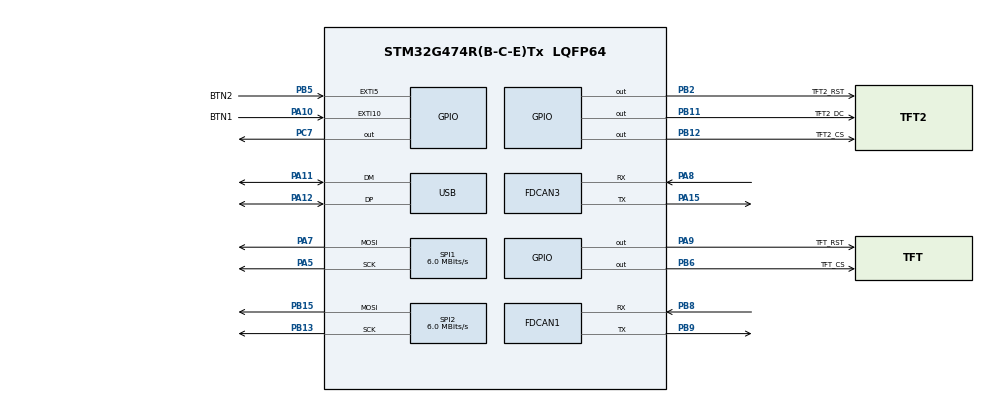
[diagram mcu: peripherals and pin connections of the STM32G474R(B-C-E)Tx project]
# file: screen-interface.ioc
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FDCAN1.CalculateBaudRateNominal=282352
FDCAN1.CalculateTimeBitNominal=3541
FDCAN1.CalculateTimeQuantumNominal=177.08333333333331
FDCAN1.NominalPrescaler=17
FDCAN1.NominalSyncJumpWidth=4
FDCAN1.NominalTimeSeg1=15
FDCAN1.NominalTimeSeg2=4
FDCAN3.CalculateBaudRateNominal=282352
FDCAN3.CalculateTimeBitNominal=3541
FDCAN3.CalculateTimeQuantumNominal=177.08333333333331
FDCAN3.NominalPrescaler=17
FDCAN3.NominalSyncJumpWidth=4
FDCAN3.NominalTimeSeg1=15
FDCAN3.NominalTimeSeg2=4
Mcu.Family=STM32G4
Mcu.Name=STM32G474R(B-C-E)Tx
Mcu.Package=LQFP64
NUCLEO-G474RE.BUTTON=1
NUCLEO-G474RE.LD2=false
NUCLEO-G474RE.VCP=true
NVIC.EXTI15_10_IRQn=true\:0\:0\:false\:false\:true\:false\:true\:true
NVIC.EXTI9_5_IRQn=true\:0\:0\:false\:false\:true\:true\:true\:true
NVIC.FDCAN1_IT0_IRQn=true\:0\:0\:false\:false\:true\:true\:true\:true
NVIC.FDCAN3_IT0_IRQn=true\:0\:0\:false\:false\:true\:true\:true\:true
NVIC.PriorityGroup=NVIC_PRIORITYGROUP_4
PA10.GPIO_Label=BTN1
PA10.GPIO_ModeDefaultEXTI=GPIO_MODE_IT_RISING
PA10.GPIO_PuPd=GPIO_PULLDOWN
PA10.Signal=GPXTI10
PA11.Mode=Device
PA11.Signal=USB_DM
PA12.Mode=Device
PA12.Signal=USB_DP
PA13.GPIO_Label=T_SWDIO
PA13.Signal=SYS_JTMS-SWDIO
PA14.GPIO_Label=T_SWCLK
PA14.Signal=SYS_JTCK-SWCLK
PA15.Mode=FDCAN_Activate
PA15.Signal=FDCAN3_TX
PA2.Signal=LPUART1_TX
PA3.Signal=LPUART1_RX
PA5.GPIO_Speed=GPIO_SPEED_FREQ_VERY_HIGH
PA5.Mode=TX_Only_Simplex_Unidirect_Master
PA5.Signal=SPI1_SCK
PA7.GPIO_Speed=GPIO_SPEED_FREQ_VERY_HIGH
PA7.Mode=TX_Only_Simplex_Unidirect_Master
PA7.Signal=SPI1_MOSI
PA8.Mode=FDCAN_Activate
PA8.Signal=FDCAN3_RX
PA9.GPIO_Label=TFT_RST
PA9.GPIO_Speed=GPIO_SPEED_FREQ_VERY_HIGH
PA9.PinState=GPIO_PIN_SET
PA9.Signal=GPIO_Output
PB11.GPIO_Label=TFT2_DC
PB11.GPIO_Speed=GPIO_SPEED_FREQ_VERY_HIGH
PB11.PinState=GPIO_PIN_SET
PB11.Signal=GPIO_Output
PB12.GPIO_Label=TFT2_CS
PB12.GPIO_Speed=GPIO_SPEED_FREQ_VERY_HIGH
PB12.PinState=GPIO_PIN_SET
PB12.Signal=GPIO_Output
PB13.GPIO_Speed=GPIO_SPEED_FREQ_VERY_HIGH
PB13.Mode=TX_Only_Simplex_Unidirect_Master
PB13.Signal=SPI2_SCK
PB15.GPIO_Speed=GPIO_SPEED_FREQ_VERY_HIGH
PB15.Mode=TX_Only_Simplex_Unidirect_Master
PB15.Signal=SPI2_MOSI
PB2.GPIO_Label=TFT2_RST
PB2.GPIO_Speed=GPIO_SPEED_FREQ_VERY_HIGH
PB2.PinState=GPIO_PIN_SET
PB2.Signal=GPIO_Output
PB3.GPIO_Label=T_SWO
PB3.Signal=SYS_JTDO-SWO
PB5.GPIO_Label=BTN2
PB5.GPIO_ModeDefaultEXTI=GPIO_MODE_IT_RISING
PB5.GPIO_PuPd=GPIO_PULLDOWN
PB5.Signal=GPXTI5
PB6.GPIO_Label=TFT_CS
PB6.GPIO_Speed=GPIO_SPEED_FREQ_VERY_HIGH
PB6.PinState=GPIO_PIN_SET
PB6.Signal=GPIO_Output
PB8-BOOT0.Mode=FDCAN_Activate
PB8-BOOT0.Signal=FDCAN1_RX
PB9.Mode=FDCAN_Activate
PB9.Signal=FDCAN1_TX
PC14-OSC32_IN.GPIO_Label=RCC_OSC32_IN
PC14-OSC32_IN.Signal=RCC_OSC32_IN
PC15-OSC32_OUT.GPIO_Label=RCC_OSC32_OUT
PC15-OSC32_OUT.Signal=RCC_OSC32_OUT
PC7.Signal=GPIO_Output
PF0-OSC_IN.GPIO_Label=RCC_OSC_IN
PF0-OSC_IN.Signal=RCC_OSC_IN
PF1-OSC_OUT.GPIO_Label=RCC_OSC_OUT
PF1-OSC_OUT.Signal=RCC_OSC_OUT
ProjectManager.HeapSize=0x200
ProjectManager.StackSize=0x400
ProjectManager.TargetToolchain=CMake
RCC.ADC12Freq_Value=96000000
RCC.ADC345Freq_Value=96000000
RCC.AHBFreq_Value=96000000
RCC.APB1Freq_Value=96000000
RCC.APB1TimFreq_Value=96000000
RCC.APB2Freq_Value=96000000
RCC.APB2TimFreq_Value=96000000
RCC.CortexFreq_Value=96000000
RCC.EXTERNAL_CLOCK_VALUE=12288000
RCC.HCLKFreq_Value=96000000
RCC.HSE_VALUE=24000000
RCC.HSI48_VALUE=48000000
RCC.HSI_VALUE=16000000
RCC.LSE_VALUE=32768
RCC.PLLN=12
RCC.PLLQ=RCC_PLLQ_DIV4
RCC.RTCClockSelection=RCC_RTCCLKSOURCE_LSE
RCC.SYSCLKFreq_VALUE=96000000
RCC.SYSCLKSource=RCC_SYSCLKSOURCE_PLLCLK
RCC.USBFreq_Value=48000000
RCC.VCOOutputFreq_Value=192000000
SPI1.BaudRatePrescaler=SPI_BAUDRATEPRESCALER_16
SPI1.CalculateBaudRate=6.0 MBits/s
SPI1.DataSize=SPI_DATASIZE_8BIT
SPI1.Direction=SPI_DIRECTION_2LINES
SPI1.Mode=SPI_MODE_MASTER
SPI1.VirtualType=VM_MASTER
SPI2.BaudRatePrescaler=SPI_BAUDRATEPRESCALER_16
SPI2.CalculateBaudRate=6.0 MBits/s
SPI2.DataSize=SPI_DATASIZE_8BIT
SPI2.Direction=SPI_DIRECTION_2LINES
SPI2.Mode=SPI_MODE_MASTER
SPI2.VirtualType=VM_MASTER
VP_NUCLEO-G474RE_VS_BSP_COMMON.Mode=COMMON
VP_SYS_VS_DBSignals.Mode=DisableDeadBatterySignals
board=NUCLEO-G474RE

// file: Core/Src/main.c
/* USER CODE BEGIN Header */
/**
  ******************************************************************************
  * @file           : main.c
  * @brief          : Main program body
  ******************************************************************************
  * @attention
  *
  * Copyright (c) 2026 STMicroelectronics.
  * All rights reserved.
  *
  * This software is licensed under terms that can be found in the LICENSE file
  * in the root directory of this software component.
  * If no LICENSE file comes with this software, it is provided AS-IS.
  *
  ******************************************************************************
  */
/* USER CODE END Header */
#include "main.h"

/* USER CODE BEGIN Includes */
#include "lvgl.h"
#include "lcd_port.h"
#include "dash_ui.h"
#include "dash_mock.h"
#include "can_bus.h"
/* USER CODE END Includes */

/* USER CODE BEGIN PD */
/* A CAN bus counts as alive if it received a frame this recently. */
#define CAN_ACTIVE_TIMEOUT_MS   500U

/* Longest the main loop sleeps, so received CAN frames are handled promptly
   and the software queues (can_bus.c) do not fill up. */
#define MAIN_LOOP_MAX_IDLE_MS   5U

#define CAN_NOTIFICATION_ID     0x123U
#define CAN_USER_BUTTON_ID_2    0x456U

/* BNO055 IMU frames, as sent by stm/can-frame-test. Standard IDs; each
   payload is three little-endian int16 raw BNO055 counts:
     0x100 accel x, y, z           100 LSB per m/s^2   (6 bytes)
     0x101 gyro  x, y, z            16 LSB per deg/s   (6 bytes)
     0x102 mag   x, y, z            16 LSB per uT      (6 bytes)
     0x103 heading, roll, pitch     16 LSB per degree, byte 6 = CALIB_STAT
           (sys | gyro | accel | mag, 2 bits each), byte 7 = 7-bit I2C
           address the IMU answered at                 (8 bytes)
   The IDs are consecutive and in dash_imu_t order. A 7-byte 0x103 (older
   sender firmware, no address) is still decoded; the address shows "0x--". */
#define CAN_ID_IMU_FIRST        0x100U
#define IMU_CALIB_FRAME_LEN     7U
#define IMU_ADDR_FRAME_LEN      8U
#define IMU_FRAME_LEN           6U

/* An IMU row shows "--" if its frame is older than this. */
#define IMU_TIMEOUT_MS          500U

/* The IMU sends at 100 Hz; redraw its readout at 10 Hz so the numbers can
   be read and the SPI link is not kept busy. */
#define IMU_UI_PERIOD_MS        100U

/* After a counted press, further edges on the same button are ignored for
   this long, so contact bounce and quick re-presses count once. */
#define BUTTON_DEBOUNCE_MS      500U
/* USER CODE END PD */

COM_InitTypeDef BspCOMInit;
FDCAN_HandleTypeDef hfdcan1;
FDCAN_HandleTypeDef hfdcan3;

SPI_HandleTypeDef hspi1;
SPI_HandleTypeDef hspi2;

/* USER CODE BEGIN PV */
/* Main display (speed, state of charge, status, IMU) on SPI1. */
static const lcd_port_t s_lcd_main = {
  .hspi = &hspi1,
  .cs_port = TFT_CS_GPIO_Port,   .cs_pin = TFT_CS_Pin,
  .dc_port = TFT_DC_GPIO_Port,   .dc_pin = TFT_DC_Pin,
  .rst_port = TFT_RST_GPIO_Port, .rst_pin = TFT_RST_Pin,
};

/* Second display (temperatures, CAN status) on SPI2. */
static const lcd_port_t s_lcd_aux = {
  .hspi = &hspi2,
  .cs_port = TFT2_CS_GPIO_Port,   .cs_pin = TFT2_CS_Pin,
  .dc_port = TFT2_DC_GPIO_Port,   .dc_pin = TFT2_DC_Pin,
  .rst_port = TFT2_RST_GPIO_Port, .rst_pin = TFT2_RST_Pin,
};

/* Latest IMU frame of each kind, raw counts. */
typedef struct
{
  int16_t  raw[3];
  uint32_t rx_tick;
  bool     seen;
} imu_sample_t;

static imu_sample_t s_imu[DASH_IMU_COUNT];
static uint8_t s_imu_calib_stat;
static int32_t s_imu_addr = DASH_NO_DATA;  /* 7-bit I2C address, from 0x103 */

/* Raw counts per unit, in dash_imu_t order. */
static const int32_t k_imu_lsb_per_unit[DASH_IMU_COUNT] = {100, 16, 16, 16};

/* Button presses counted by the EXTI interrupt (BTN1 = PA10, BTN2 = PB5),
   in dash_btn_t order. Written only in the interrupt, read in the main loop. */
static volatile uint32_t s_btn_count[DASH_BTN_COUNT];
/* Tick of the last counted press. Starts one debounce period in the past so
   a press right after reset still counts. */
static uint32_t s_btn_last_ms[DASH_BTN_COUNT] = {
  0U - BUTTON_DEBOUNCE_MS, 0U - BUTTON_DEBOUNCE_MS,
};
/* USER CODE END PV */

void SystemClock_Config(void);
static void MX_GPIO_Init(void);
static void MX_SPI1_Init(void);
static void MX_FDCAN1_Init(void);
static void MX_FDCAN3_Init(void);
static void MX_SPI2_Init(void);
/* USER CODE BEGIN PFP */
static void gui_init(void);
static void can_poll(void);
static void handle_can_frame(can_bus_t bus, const can_frame_t *frame);
static bool handle_imu_frame(const can_frame_t *frame);
static void imu_show(void);
static void buttons_show(void);
/* USER CODE END PFP */

int main(void)
{

  /* MCU Configuration--------------------------------------------------------*/

  /* Reset of all peripherals, Initializes the Flash interface and the Systick. */
  HAL_Init();

  /* Configure the system clock */
  SystemClock_Config();

  /* Initialize all configured peripherals */
  MX_GPIO_Init();
  MX_SPI1_Init();
  MX_FDCAN1_Init();
  MX_FDCAN3_Init();
  MX_SPI2_Init();
  /* USER CODE BEGIN 2 */
  gui_init();

  if (!can_bus_init(&hfdcan1, &hfdcan3))
  {
    Error_Handler();
  }
  /* USER CODE END 2 */

  /* Initialize USER push-button, will be used to trigger an interrupt each time it's pressed.*/
  BSP_PB_Init(BUTTON_USER, BUTTON_MODE_EXTI);

  /* Initialize COM1 port (115200, 8 bits (7-bit data + 1 stop bit), no parity */
  BspCOMInit.BaudRate   = 115200;
  BspCOMInit.WordLength = COM_WORDLENGTH_8B;
  BspCOMInit.StopBits   = COM_STOPBITS_1;
  BspCOMInit.Parity     = COM_PARITY_NONE;
  BspCOMInit.HwFlowCtl  = COM_HWCONTROL_NONE;
  if (BSP_COM_Init(COM1, &BspCOMInit) != BSP_ERROR_NONE)
  {
    Error_Handler();
  }

  /* Infinite loop */
  while (1)
  {

    /* USER CODE BEGIN 3 */
    can_poll();
    buttons_show();

    /* Runs LVGL's timers: refresh of both screens and the dashboard's mock
       data. Sleep until the next one is due, but not so long that CAN frames
       pile up. */
    uint32_t idle_ms = lv_timer_handler();

    if ((idle_ms == LV_NO_TIMER_READY) || (idle_ms > MAIN_LOOP_MAX_IDLE_MS))
    {
      idle_ms = MAIN_LOOP_MAX_IDLE_MS;
    }
    HAL_Delay(idle_ms);
  }
  /* USER CODE END 3 */
}

void SystemClock_Config(void)
{
  RCC_OscInitTypeDef RCC_OscInitStruct = {0};
  RCC_ClkInitTypeDef RCC_ClkInitStruct = {0};

  /** Configure the main internal regulator output voltage
  */
  HAL_PWREx_ControlVoltageScaling(PWR_REGULATOR_VOLTAGE_SCALE1_BOOST);

  /** Initializes the RCC Oscillators according to the specified parameters
  * in the RCC_OscInitTypeDef structure.
  */
  RCC_OscInitStruct.OscillatorType = RCC_OSCILLATORTYPE_HSI;
  RCC_OscInitStruct.HSIState = RCC_HSI_ON;
  RCC_OscInitStruct.HSICalibrationValue = RCC_HSICALIBRATION_DEFAULT;
  RCC_OscInitStruct.PLL.PLLState = RCC_PLL_ON;
  RCC_OscInitStruct.PLL.PLLSource = RCC_PLLSOURCE_HSI;
  RCC_OscInitStruct.PLL.PLLM = RCC_PLLM_DIV4;
  RCC_OscInitStruct.PLL.PLLN = 85;
  RCC_OscInitStruct.PLL.PLLP = RCC_PLLP_DIV2;
  RCC_OscInitStruct.PLL.PLLQ = RCC_PLLQ_DIV2;
  RCC_OscInitStruct.PLL.PLLR = RCC_PLLR_DIV2;
  if (HAL_RCC_OscConfig(&RCC_OscInitStruct) != HAL_OK)
  {
    Error_Handler();
  }

  /** Initializes the CPU, AHB and APB buses clocks
  */
  RCC_ClkInitStruct.ClockType = RCC_CLOCKTYPE_HCLK|RCC_CLOCKTYPE_SYSCLK
                              |RCC_CLOCKTYPE_PCLK1|RCC_CLOCKTYPE_PCLK2;
  RCC_ClkInitStruct.SYSCLKSource = RCC_SYSCLKSOURCE_PLLCLK;
  RCC_ClkInitStruct.AHBCLKDivider = RCC_SYSCLK_DIV1;
  RCC_ClkInitStruct.APB1CLKDivider = RCC_HCLK_DIV1;
  RCC_ClkInitStruct.APB2CLKDivider = RCC_HCLK_DIV1;

  if (HAL_RCC_ClockConfig(&RCC_ClkInitStruct, FLASH_LATENCY_4) != HAL_OK)
  {
    Error_Handler();
  }
}

static void MX_FDCAN1_Init(void)
{

  hfdcan1.Instance = FDCAN1;
  hfdcan1.Init.ClockDivider = FDCAN_CLOCK_DIV1;
  hfdcan1.Init.FrameFormat = FDCAN_FRAME_CLASSIC;
  hfdcan1.Init.Mode = FDCAN_MODE_NORMAL;
  hfdcan1.Init.AutoRetransmission = DISABLE;
  hfdcan1.Init.TransmitPause = DISABLE;
  hfdcan1.Init.ProtocolException = DISABLE;
  hfdcan1.Init.NominalPrescaler = 17;
  hfdcan1.Init.NominalSyncJumpWidth = 4;
  hfdcan1.Init.NominalTimeSeg1 = 15;
  hfdcan1.Init.NominalTimeSeg2 = 4;
  hfdcan1.Init.DataPrescaler = 1;
  hfdcan1.Init.DataSyncJumpWidth = 1;
  hfdcan1.Init.DataTimeSeg1 = 1;
  hfdcan1.Init.DataTimeSeg2 = 1;
  hfdcan1.Init.StdFiltersNbr = 0;
  hfdcan1.Init.ExtFiltersNbr = 0;
  hfdcan1.Init.TxFifoQueueMode = FDCAN_TX_FIFO_OPERATION;
  if (HAL_FDCAN_Init(&hfdcan1) != HAL_OK)
  {
    Error_Handler();
  }

}

static void MX_FDCAN3_Init(void)
{

  hfdcan3.Instance = FDCAN3;
  hfdcan3.Init.ClockDivider = FDCAN_CLOCK_DIV1;
  hfdcan3.Init.FrameFormat = FDCAN_FRAME_CLASSIC;
  hfdcan3.Init.Mode = FDCAN_MODE_NORMAL;
  hfdcan3.Init.AutoRetransmission = DISABLE;
  hfdcan3.Init.TransmitPause = DISABLE;
  hfdcan3.Init.ProtocolException = DISABLE;
  hfdcan3.Init.NominalPrescaler = 17;
  hfdcan3.Init.NominalSyncJumpWidth = 4;
  hfdcan3.Init.NominalTimeSeg1 = 15;
  hfdcan3.Init.NominalTimeSeg2 = 4;
  hfdcan3.Init.DataPrescaler = 1;
  hfdcan3.Init.DataSyncJumpWidth = 1;
  hfdcan3.Init.DataTimeSeg1 = 1;
  hfdcan3.Init.DataTimeSeg2 = 1;
  hfdcan3.Init.StdFiltersNbr = 0;
  hfdcan3.Init.ExtFiltersNbr = 0;
  hfdcan3.Init.TxFifoQueueMode = FDCAN_TX_FIFO_OPERATION;
  if (HAL_FDCAN_Init(&hfdcan3) != HAL_OK)
  {
    Error_Handler();
  }

}

static void MX_SPI1_Init(void)
{

  /* SPI1 parameter configuration*/
  hspi1.Instance = SPI1;
  hspi1.Init.Mode = SPI_MODE_MASTER;
  hspi1.Init.Direction = SPI_DIRECTION_2LINES;
  hspi1.Init.DataSize = SPI_DATASIZE_8BIT;
  hspi1.Init.CLKPolarity = SPI_POLARITY_LOW;
  hspi1.Init.CLKPhase = SPI_PHASE_1EDGE;
  hspi1.Init.NSS = SPI_NSS_SOFT;
  hspi1.Init.BaudRatePrescaler = SPI_BAUDRATEPRESCALER_16;
  hspi1.Init.FirstBit = SPI_FIRSTBIT_MSB;
  hspi1.Init.TIMode = SPI_TIMODE_DISABLE;
  hspi1.Init.CRCCalculation = SPI_CRCCALCULATION_DISABLE;
  hspi1.Init.CRCPolynomial = 7;
  hspi1.Init.CRCLength = SPI_CRC_LENGTH_DATASIZE;
  hspi1.Init.NSSPMode = SPI_NSS_PULSE_ENABLE;
  if (HAL_SPI_Init(&hspi1) != HAL_OK)
  {
    Error_Handler();
  }

}

static void MX_SPI2_Init(void)
{

  /* SPI2 parameter configuration*/
  hspi2.Instance = SPI2;
  hspi2.Init.Mode = SPI_MODE_MASTER;
  hspi2.Init.Direction = SPI_DIRECTION_2LINES;
  hspi2.Init.DataSize = SPI_DATASIZE_8BIT;
  hspi2.Init.CLKPolarity = SPI_POLARITY_LOW;
  hspi2.Init.CLKPhase = SPI_PHASE_1EDGE;
  hspi2.Init.NSS = SPI_NSS_SOFT;
  hspi2.Init.BaudRatePrescaler = SPI_BAUDRATEPRESCALER_16;
  hspi2.Init.FirstBit = SPI_FIRSTBIT_MSB;
  hspi2.Init.TIMode = SPI_TIMODE_DISABLE;
  hspi2.Init.CRCCalculation = SPI_CRCCALCULATION_DISABLE;
  hspi2.Init.CRCPolynomial = 7;
  hspi2.Init.CRCLength = SPI_CRC_LENGTH_DATASIZE;
  hspi2.Init.NSSPMode = SPI_NSS_PULSE_ENABLE;
  if (HAL_SPI_Init(&hspi2) != HAL_OK)
  {
    Error_Handler();
  }

}

static void MX_GPIO_Init(void)
{
  GPIO_InitTypeDef GPIO_InitStruct = {0};

  /* GPIO Ports Clock Enable */
  __HAL_RCC_GPIOC_CLK_ENABLE();
  __HAL_RCC_GPIOF_CLK_ENABLE();
  __HAL_RCC_GPIOA_CLK_ENABLE();
  __HAL_RCC_GPIOB_CLK_ENABLE();

  /*Configure GPIO pin Output Level */
  HAL_GPIO_WritePin(GPIOB, TFT2_RST_Pin|TFT2_DC_Pin|TFT2_CS_Pin|TFT_CS_Pin, GPIO_PIN_SET);

  /*Configure GPIO pin Output Level */
  HAL_GPIO_WritePin(TFT_DC_GPIO_Port, TFT_DC_Pin, GPIO_PIN_SET);

  /*Configure GPIO pin Output Level */
  HAL_GPIO_WritePin(TFT_RST_GPIO_Port, TFT_RST_Pin, GPIO_PIN_SET);

  /*Configure GPIO pins : TFT2_RST_Pin TFT2_DC_Pin TFT2_CS_Pin TFT_CS_Pin */
  GPIO_InitStruct.Pin = TFT2_RST_Pin|TFT2_DC_Pin|TFT2_CS_Pin|TFT_CS_Pin;
  GPIO_InitStruct.Mode = GPIO_MODE_OUTPUT_PP;
  GPIO_InitStruct.Pull = GPIO_NOPULL;
  GPIO_InitStruct.Speed = GPIO_SPEED_FREQ_VERY_HIGH;
  HAL_GPIO_Init(GPIOB, &GPIO_InitStruct);

  /*Configure GPIO pin : TFT_DC_Pin */
  GPIO_InitStruct.Pin = TFT_DC_Pin;
  GPIO_InitStruct.Mode = GPIO_MODE_OUTPUT_PP;
  GPIO_InitStruct.Pull = GPIO_NOPULL;
  GPIO_InitStruct.Speed = GPIO_SPEED_FREQ_VERY_HIGH;
  HAL_GPIO_Init(TFT_DC_GPIO_Port, &GPIO_InitStruct);

  /*Configure GPIO pin : TFT_RST_Pin */
  GPIO_InitStruct.Pin = TFT_RST_Pin;
  GPIO_InitStruct.Mode = GPIO_MODE_OUTPUT_PP;
  GPIO_InitStruct.Pull = GPIO_NOPULL;
  GPIO_InitStruct.Speed = GPIO_SPEED_FREQ_VERY_HIGH;
  HAL_GPIO_Init(TFT_RST_GPIO_Port, &GPIO_InitStruct);

  /*Configure GPIO pin : BTN1_Pin */
  GPIO_InitStruct.Pin = BTN1_Pin;
  GPIO_InitStruct.Mode = GPIO_MODE_IT_RISING;
  GPIO_InitStruct.Pull = GPIO_PULLDOWN;
  HAL_GPIO_Init(BTN1_GPIO_Port, &GPIO_InitStruct);

  /*Configure GPIO pin : BTN2_Pin */
  GPIO_InitStruct.Pin = BTN2_Pin;
  GPIO_InitStruct.Mode = GPIO_MODE_IT_RISING;
  GPIO_InitStruct.Pull = GPIO_PULLDOWN;
  HAL_GPIO_Init(BTN2_GPIO_Port, &GPIO_InitStruct);

  /* EXTI interrupt init*/
  HAL_NVIC_SetPriority(EXTI9_5_IRQn, 0, 0);
  HAL_NVIC_EnableIRQ(EXTI9_5_IRQn);

  HAL_NVIC_SetPriority(EXTI15_10_IRQn, 0, 0);
  HAL_NVIC_EnableIRQ(EXTI15_10_IRQn);

}

/* USER CODE BEGIN 4 */
/* LVGL porting steps: init, tick source, display drivers, then the UI. */
static void gui_init(void)
{
  lv_display_t *main_disp;
  lv_display_t *aux_disp;

  lv_init();
  lv_tick_set_cb(HAL_GetTick);   /* SysTick already counts milliseconds */
  lv_delay_set_cb(HAL_Delay);    /* used by the ILI9341 init sequence */

  main_disp = lcd_port_init(&s_lcd_main);
  aux_disp = lcd_port_init(&s_lcd_aux);
  if ((main_disp == NULL) || (aux_disp == NULL))
  {
    Error_Handler();
  }

  dash_ui_create(main_disp, aux_disp);
  dash_mock_start();
}

/* Handle every CAN frame received since the last pass and show which buses
   are alive. Runs in the main loop, so it may call the dash_ui setters. */
static void can_poll(void)
{
  static uint32_t rx_count;   /* frames received on both buses since reset */
  static uint32_t imu_count;
  static uint32_t user_count;
  can_frame_t frame;

  can_bus_service();

  for (can_bus_t bus = CAN_BUS_1; bus < CAN_BUS_COUNT; bus++)
  {
    while (can_bus_receive(bus, &frame))
    {
      handle_can_frame(bus, &frame);
      rx_count++;
      if (!frame.extended)
      {
        if ((frame.id >= CAN_ID_IMU_FIRST) &&
            (frame.id < (CAN_ID_IMU_FIRST + (uint32_t)DASH_IMU_COUNT)))
        {
          imu_count++;
        }
        else if ((frame.id == CAN_NOTIFICATION_ID) || (frame.id == CAN_USER_BUTTON_ID_2))
        {
          user_count++;
        }
      }
    }
  }

  dash_ui_set_can_rx_counts(rx_count, imu_count, user_count);
  imu_show();

  dash_ui_set_can_status(can_bus_is_active(CAN_BUS_1, CAN_ACTIVE_TIMEOUT_MS),
                         can_bus_is_active(CAN_BUS_2, CAN_ACTIVE_TIMEOUT_MS));
}

/* Decode the car's frames here and pass the values to the dash_ui_set_*()
   setters, then remove dash_mock_start() from gui_init(). */
static void handle_can_frame(can_bus_t bus, const can_frame_t *frame)
{
  (void)bus;

  if (handle_imu_frame(frame))
  {
    return;
  }

  if (!frame->extended && (frame->id == CAN_NOTIFICATION_ID) &&
      (frame->len == 8U) &&
      (frame->data[0] == 0xFFU) &&
      (frame->data[1] == 0x00U) &&
      (frame->data[2] == 0xFFU) &&
      (frame->data[3] == 0x00U) &&
      (frame->data[4] == 0xFFU) &&
      (frame->data[5] == 0x00U) &&
      (frame->data[6] == 0xFFU) &&
      (frame->data[7] == 0x00U))
  {
    dash_ui_show_can_notification();
  }
}

/* Store an IMU frame (IDs 0x100..0x103, from either bus). Returns false if
   `frame` is not one. */
static bool handle_imu_frame(const can_frame_t *frame)
{
  uint32_t row;
  imu_sample_t *s;

  if (frame->extended || (frame->id < CAN_ID_IMU_FIRST) ||
      (frame->id >= (CAN_ID_IMU_FIRST + (uint32_t)DASH_IMU_COUNT)))
  {
    return false;
  }
  row = frame->id - CAN_ID_IMU_FIRST;
  if (frame->len < ((row == (uint32_t)DASH_IMU_EULER) ? IMU_CALIB_FRAME_LEN : IMU_FRAME_LEN))
  {
    return true;  /* an IMU ID, but too short to decode */
  }

  s = &s_imu[row];
  for (uint32_t i = 0U; i < 3U; i++)
  {
    s->raw[i] = (int16_t)((uint16_t)frame->data[2U * i] | ((uint16_t)frame->data[(2U * i) + 1U] << 8));
  }
  if (row == (uint32_t)DASH_IMU_EULER)
  {
    s_imu_calib_stat = frame->data[6];
    /* The sender uses 0 for "no IMU". */
    s_imu_addr = ((frame->len >= IMU_ADDR_FRAME_LEN) && (frame->data[7] != 0U))
                 ? (int32_t)frame->data[7] : DASH_NO_DATA;
  }
  s->rx_tick = frame->rx_tick;
  s->seen = true;
  return true;
}

/* Raw counts to tenths of a unit, rounded to nearest. */
static int32_t imu_to_tenths(int16_t raw, int32_t lsb_per_unit)
{
  const int32_t n = (int32_t)raw * 10;

  return (n >= 0) ? ((n + (lsb_per_unit / 2)) / lsb_per_unit)
                  : -((-n + (lsb_per_unit / 2)) / lsb_per_unit);
}

/* Update the IMU readout every IMU_UI_PERIOD_MS. A row whose frame stopped
   arriving shows "--". */
static void imu_show(void)
{
  static uint32_t last_ms;
  const uint32_t now = HAL_GetTick();

  if ((now - last_ms) < IMU_UI_PERIOD_MS)
  {
    return;
  }
  last_ms = now;

  for (uint32_t row = 0U; row < (uint32_t)DASH_IMU_COUNT; row++)
  {
    const imu_sample_t *s = &s_imu[row];
    const int32_t lsb = k_imu_lsb_per_unit[row];

    if (s->seen && ((now - s->rx_tick) < IMU_TIMEOUT_MS))
    {
      dash_ui_set_imu((dash_imu_t)row, imu_to_tenths(s->raw[0], lsb),
                      imu_to_tenths(s->raw[1], lsb), imu_to_tenths(s->raw[2], lsb));
    }
    else
    {
      dash_ui_set_imu((dash_imu_t)row, DASH_NO_DATA, DASH_NO_DATA, DASH_NO_DATA);
    }
  }

  if (s_imu[DASH_IMU_EULER].seen && ((now - s_imu[DASH_IMU_EULER].rx_tick) < IMU_TIMEOUT_MS))
  {
    dash_ui_set_imu_calib((int32_t)((s_imu_calib_stat >> 6) & 0x3U));  /* system level */
    dash_ui_set_imu_addr(s_imu_addr);
  }
  else
  {
    dash_ui_set_imu_calib(DASH_NO_DATA);
    dash_ui_set_imu_addr(DASH_NO_DATA);
  }
}

/* Rising edge on a button pin (EXTI interrupt). Counts a press unless the
   same button was counted less than BUTTON_DEBOUNCE_MS ago. */
void HAL_GPIO_EXTI_Callback(uint16_t GPIO_Pin)
{
  const uint32_t now = HAL_GetTick();
  dash_btn_t btn;

  if (GPIO_Pin == BTN1_Pin)
  {
    btn = DASH_BTN_PA10;
  }
  else if (GPIO_Pin == BTN2_Pin)
  {
    btn = DASH_BTN_PB5;
  }
  else
  {
    return;
  }

  if ((now - s_btn_last_ms[btn]) >= BUTTON_DEBOUNCE_MS)
  {
    s_btn_last_ms[btn] = now;
    s_btn_count[btn]++;
  }
}

/* Show the press counts. Runs in the main loop because LVGL must not be
   called from an interrupt. */
static void buttons_show(void)
{
  for (uint32_t i = 0U; i < (uint32_t)DASH_BTN_COUNT; i++)
  {
    dash_ui_set_button_count((dash_btn_t)i, s_btn_count[i]);
  }
}
/* USER CODE END 4 */

void Error_Handler(void)
{
  __disable_irq();
  while (1)
  {
  }
}
